VERSION 5.7 ;
BUSBITCHARS "[]" ;
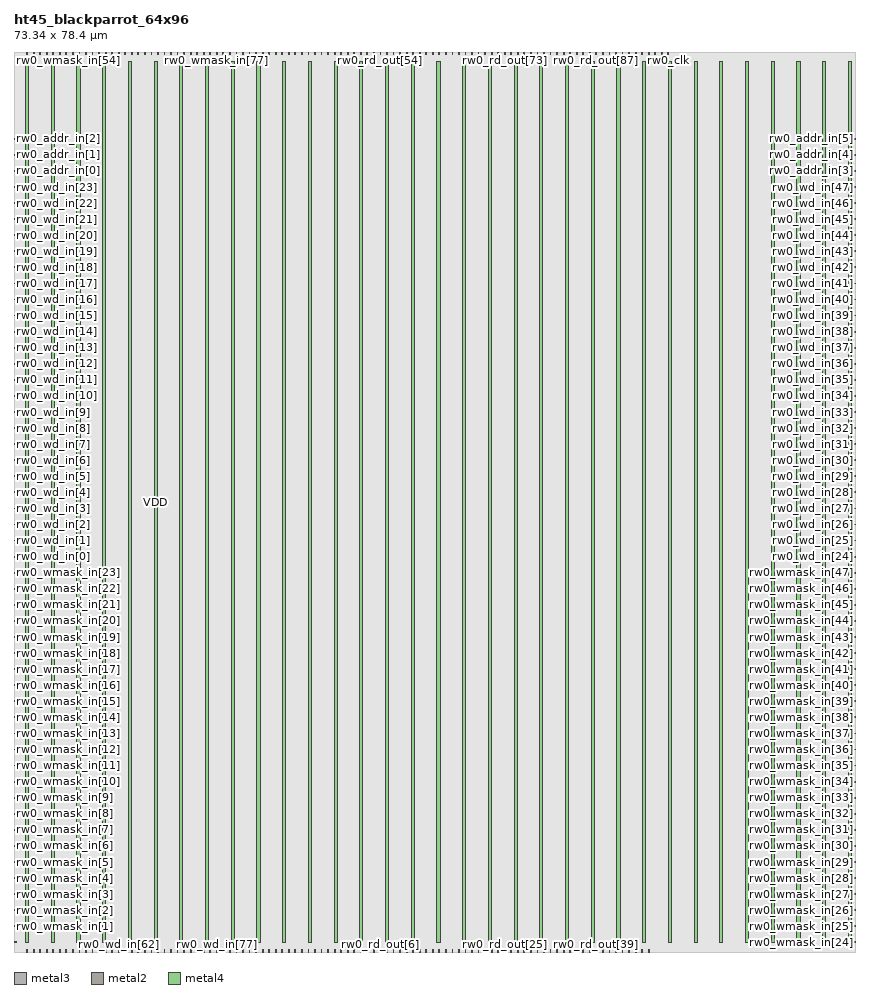
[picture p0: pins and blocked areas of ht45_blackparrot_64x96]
MACRO ht45_blackparrot_64x96
  FOREIGN ht45_blackparrot_64x96 0 0 ;
  SYMMETRY X Y R90 ;
  SIZE 73.340 BY 78.400 ;
  CLASS BLOCK ;
  PIN rw0_wmask_in[0]
    DIRECTION INPUT ;
    USE SIGNAL ;
    SHAPE ABUTMENT ;
    PORT
      LAYER metal3 ;
      RECT 0.000 0.805 0.210 0.875 ;
    END
  END rw0_wmask_in[0]
  PIN rw0_wmask_in[1]
    DIRECTION INPUT ;
    USE SIGNAL ;
    SHAPE ABUTMENT ;
    PORT
      LAYER metal3 ;
      RECT 0.000 2.205 0.210 2.275 ;
    END
  END rw0_wmask_in[1]
  PIN rw0_wmask_in[2]
    DIRECTION INPUT ;
    USE SIGNAL ;
    SHAPE ABUTMENT ;
    PORT
      LAYER metal3 ;
      RECT 0.000 3.605 0.210 3.675 ;
    END
  END rw0_wmask_in[2]
  PIN rw0_wmask_in[3]
    DIRECTION INPUT ;
    USE SIGNAL ;
    SHAPE ABUTMENT ;
    PORT
      LAYER metal3 ;
      RECT 0.000 5.005 0.210 5.075 ;
    END
  END rw0_wmask_in[3]
  PIN rw0_wmask_in[4]
    DIRECTION INPUT ;
    USE SIGNAL ;
    SHAPE ABUTMENT ;
    PORT
      LAYER metal3 ;
      RECT 0.000 6.405 0.210 6.475 ;
    END
  END rw0_wmask_in[4]
  PIN rw0_wmask_in[5]
    DIRECTION INPUT ;
    USE SIGNAL ;
    SHAPE ABUTMENT ;
    PORT
      LAYER metal3 ;
      RECT 0.000 7.805 0.210 7.875 ;
    END
  END rw0_wmask_in[5]
  PIN rw0_wmask_in[6]
    DIRECTION INPUT ;
    USE SIGNAL ;
    SHAPE ABUTMENT ;
    PORT
      LAYER metal3 ;
      RECT 0.000 9.205 0.210 9.275 ;
    END
  END rw0_wmask_in[6]
  PIN rw0_wmask_in[7]
    DIRECTION INPUT ;
    USE SIGNAL ;
    SHAPE ABUTMENT ;
    PORT
      LAYER metal3 ;
      RECT 0.000 10.605 0.210 10.675 ;
    END
  END rw0_wmask_in[7]
  PIN rw0_wmask_in[8]
    DIRECTION INPUT ;
    USE SIGNAL ;
    SHAPE ABUTMENT ;
    PORT
      LAYER metal3 ;
      RECT 0.000 12.005 0.210 12.075 ;
    END
  END rw0_wmask_in[8]
  PIN rw0_wmask_in[9]
    DIRECTION INPUT ;
    USE SIGNAL ;
    SHAPE ABUTMENT ;
    PORT
      LAYER metal3 ;
      RECT 0.000 13.405 0.210 13.475 ;
    END
  END rw0_wmask_in[9]
  PIN rw0_wmask_in[10]
    DIRECTION INPUT ;
    USE SIGNAL ;
    SHAPE ABUTMENT ;
    PORT
      LAYER metal3 ;
      RECT 0.000 14.805 0.210 14.875 ;
    END
  END rw0_wmask_in[10]
  PIN rw0_wmask_in[11]
    DIRECTION INPUT ;
    USE SIGNAL ;
    SHAPE ABUTMENT ;
    PORT
      LAYER metal3 ;
      RECT 0.000 16.205 0.210 16.275 ;
    END
  END rw0_wmask_in[11]
  PIN rw0_wmask_in[12]
    DIRECTION INPUT ;
    USE SIGNAL ;
    SHAPE ABUTMENT ;
    PORT
      LAYER metal3 ;
      RECT 0.000 17.605 0.210 17.675 ;
    END
  END rw0_wmask_in[12]
  PIN rw0_wmask_in[13]
    DIRECTION INPUT ;
    USE SIGNAL ;
    SHAPE ABUTMENT ;
    PORT
      LAYER metal3 ;
      RECT 0.000 19.005 0.210 19.075 ;
    END
  END rw0_wmask_in[13]
  PIN rw0_wmask_in[14]
    DIRECTION INPUT ;
    USE SIGNAL ;
    SHAPE ABUTMENT ;
    PORT
      LAYER metal3 ;
      RECT 0.000 20.405 0.210 20.475 ;
    END
  END rw0_wmask_in[14]
  PIN rw0_wmask_in[15]
    DIRECTION INPUT ;
    USE SIGNAL ;
    SHAPE ABUTMENT ;
    PORT
      LAYER metal3 ;
      RECT 0.000 21.805 0.210 21.875 ;
    END
  END rw0_wmask_in[15]
  PIN rw0_wmask_in[16]
    DIRECTION INPUT ;
    USE SIGNAL ;
    SHAPE ABUTMENT ;
    PORT
      LAYER metal3 ;
      RECT 0.000 23.205 0.210 23.275 ;
    END
  END rw0_wmask_in[16]
  PIN rw0_wmask_in[17]
    DIRECTION INPUT ;
    USE SIGNAL ;
    SHAPE ABUTMENT ;
    PORT
      LAYER metal3 ;
      RECT 0.000 24.605 0.210 24.675 ;
    END
  END rw0_wmask_in[17]
  PIN rw0_wmask_in[18]
    DIRECTION INPUT ;
    USE SIGNAL ;
    SHAPE ABUTMENT ;
    PORT
      LAYER metal3 ;
      RECT 0.000 26.005 0.210 26.075 ;
    END
  END rw0_wmask_in[18]
  PIN rw0_wmask_in[19]
    DIRECTION INPUT ;
    USE SIGNAL ;
    SHAPE ABUTMENT ;
    PORT
      LAYER metal3 ;
      RECT 0.000 27.405 0.210 27.475 ;
    END
  END rw0_wmask_in[19]
  PIN rw0_wmask_in[20]
    DIRECTION INPUT ;
    USE SIGNAL ;
    SHAPE ABUTMENT ;
    PORT
      LAYER metal3 ;
      RECT 0.000 28.805 0.210 28.875 ;
    END
  END rw0_wmask_in[20]
  PIN rw0_wmask_in[21]
    DIRECTION INPUT ;
    USE SIGNAL ;
    SHAPE ABUTMENT ;
    PORT
      LAYER metal3 ;
      RECT 0.000 30.205 0.210 30.275 ;
    END
  END rw0_wmask_in[21]
  PIN rw0_wmask_in[22]
    DIRECTION INPUT ;
    USE SIGNAL ;
    SHAPE ABUTMENT ;
    PORT
      LAYER metal3 ;
      RECT 0.000 31.605 0.210 31.675 ;
    END
  END rw0_wmask_in[22]
  PIN rw0_wmask_in[23]
    DIRECTION INPUT ;
    USE SIGNAL ;
    SHAPE ABUTMENT ;
    PORT
      LAYER metal3 ;
      RECT 0.000 33.005 0.210 33.075 ;
    END
  END rw0_wmask_in[23]
  PIN rw0_wmask_in[24]
    DIRECTION INPUT ;
    USE SIGNAL ;
    SHAPE ABUTMENT ;
    PORT
      LAYER metal3 ;
      RECT 73.130 0.805 73.340 0.875 ;
    END
  END rw0_wmask_in[24]
  PIN rw0_wmask_in[25]
    DIRECTION INPUT ;
    USE SIGNAL ;
    SHAPE ABUTMENT ;
    PORT
      LAYER metal3 ;
      RECT 73.130 2.205 73.340 2.275 ;
    END
  END rw0_wmask_in[25]
  PIN rw0_wmask_in[26]
    DIRECTION INPUT ;
    USE SIGNAL ;
    SHAPE ABUTMENT ;
    PORT
      LAYER metal3 ;
      RECT 73.130 3.605 73.340 3.675 ;
    END
  END rw0_wmask_in[26]
  PIN rw0_wmask_in[27]
    DIRECTION INPUT ;
    USE SIGNAL ;
    SHAPE ABUTMENT ;
    PORT
      LAYER metal3 ;
      RECT 73.130 5.005 73.340 5.075 ;
    END
  END rw0_wmask_in[27]
  PIN rw0_wmask_in[28]
    DIRECTION INPUT ;
    USE SIGNAL ;
    SHAPE ABUTMENT ;
    PORT
      LAYER metal3 ;
      RECT 73.130 6.405 73.340 6.475 ;
    END
  END rw0_wmask_in[28]
  PIN rw0_wmask_in[29]
    DIRECTION INPUT ;
    USE SIGNAL ;
    SHAPE ABUTMENT ;
    PORT
      LAYER metal3 ;
      RECT 73.130 7.805 73.340 7.875 ;
    END
  END rw0_wmask_in[29]
  PIN rw0_wmask_in[30]
    DIRECTION INPUT ;
    USE SIGNAL ;
    SHAPE ABUTMENT ;
    PORT
      LAYER metal3 ;
      RECT 73.130 9.205 73.340 9.275 ;
    END
  END rw0_wmask_in[30]
  PIN rw0_wmask_in[31]
    DIRECTION INPUT ;
    USE SIGNAL ;
    SHAPE ABUTMENT ;
    PORT
      LAYER metal3 ;
      RECT 73.130 10.605 73.340 10.675 ;
    END
  END rw0_wmask_in[31]
  PIN rw0_wmask_in[32]
    DIRECTION INPUT ;
    USE SIGNAL ;
    SHAPE ABUTMENT ;
    PORT
      LAYER metal3 ;
      RECT 73.130 12.005 73.340 12.075 ;
    END
  END rw0_wmask_in[32]
  PIN rw0_wmask_in[33]
    DIRECTION INPUT ;
    USE SIGNAL ;
    SHAPE ABUTMENT ;
    PORT
      LAYER metal3 ;
      RECT 73.130 13.405 73.340 13.475 ;
    END
  END rw0_wmask_in[33]
  PIN rw0_wmask_in[34]
    DIRECTION INPUT ;
    USE SIGNAL ;
    SHAPE ABUTMENT ;
    PORT
      LAYER metal3 ;
      RECT 73.130 14.805 73.340 14.875 ;
    END
  END rw0_wmask_in[34]
  PIN rw0_wmask_in[35]
    DIRECTION INPUT ;
    USE SIGNAL ;
    SHAPE ABUTMENT ;
    PORT
      LAYER metal3 ;
      RECT 73.130 16.205 73.340 16.275 ;
    END
  END rw0_wmask_in[35]
  PIN rw0_wmask_in[36]
    DIRECTION INPUT ;
    USE SIGNAL ;
    SHAPE ABUTMENT ;
    PORT
      LAYER metal3 ;
      RECT 73.130 17.605 73.340 17.675 ;
    END
  END rw0_wmask_in[36]
  PIN rw0_wmask_in[37]
    DIRECTION INPUT ;
    USE SIGNAL ;
    SHAPE ABUTMENT ;
    PORT
      LAYER metal3 ;
      RECT 73.130 19.005 73.340 19.075 ;
    END
  END rw0_wmask_in[37]
  PIN rw0_wmask_in[38]
    DIRECTION INPUT ;
    USE SIGNAL ;
    SHAPE ABUTMENT ;
    PORT
      LAYER metal3 ;
      RECT 73.130 20.405 73.340 20.475 ;
    END
  END rw0_wmask_in[38]
  PIN rw0_wmask_in[39]
    DIRECTION INPUT ;
    USE SIGNAL ;
    SHAPE ABUTMENT ;
    PORT
      LAYER metal3 ;
      RECT 73.130 21.805 73.340 21.875 ;
    END
  END rw0_wmask_in[39]
  PIN rw0_wmask_in[40]
    DIRECTION INPUT ;
    USE SIGNAL ;
    SHAPE ABUTMENT ;
    PORT
      LAYER metal3 ;
      RECT 73.130 23.205 73.340 23.275 ;
    END
  END rw0_wmask_in[40]
  PIN rw0_wmask_in[41]
    DIRECTION INPUT ;
    USE SIGNAL ;
    SHAPE ABUTMENT ;
    PORT
      LAYER metal3 ;
      RECT 73.130 24.605 73.340 24.675 ;
    END
  END rw0_wmask_in[41]
  PIN rw0_wmask_in[42]
    DIRECTION INPUT ;
    USE SIGNAL ;
    SHAPE ABUTMENT ;
    PORT
      LAYER metal3 ;
      RECT 73.130 26.005 73.340 26.075 ;
    END
  END rw0_wmask_in[42]
  PIN rw0_wmask_in[43]
    DIRECTION INPUT ;
    USE SIGNAL ;
    SHAPE ABUTMENT ;
    PORT
      LAYER metal3 ;
      RECT 73.130 27.405 73.340 27.475 ;
    END
  END rw0_wmask_in[43]
  PIN rw0_wmask_in[44]
    DIRECTION INPUT ;
    USE SIGNAL ;
    SHAPE ABUTMENT ;
    PORT
      LAYER metal3 ;
      RECT 73.130 28.805 73.340 28.875 ;
    END
  END rw0_wmask_in[44]
  PIN rw0_wmask_in[45]
    DIRECTION INPUT ;
    USE SIGNAL ;
    SHAPE ABUTMENT ;
    PORT
      LAYER metal3 ;
      RECT 73.130 30.205 73.340 30.275 ;
    END
  END rw0_wmask_in[45]
  PIN rw0_wmask_in[46]
    DIRECTION INPUT ;
    USE SIGNAL ;
    SHAPE ABUTMENT ;
    PORT
      LAYER metal3 ;
      RECT 73.130 31.605 73.340 31.675 ;
    END
  END rw0_wmask_in[46]
  PIN rw0_wmask_in[47]
    DIRECTION INPUT ;
    USE SIGNAL ;
    SHAPE ABUTMENT ;
    PORT
      LAYER metal3 ;
      RECT 73.130 33.005 73.340 33.075 ;
    END
  END rw0_wmask_in[47]
  PIN rw0_wmask_in[48]
    DIRECTION INPUT ;
    USE SIGNAL ;
    SHAPE ABUTMENT ;
    PORT
      LAYER metal2 ;
      RECT 1.105 78.190 1.175 78.400 ;
    END
  END rw0_wmask_in[48]
  PIN rw0_wmask_in[49]
    DIRECTION INPUT ;
    USE SIGNAL ;
    SHAPE ABUTMENT ;
    PORT
      LAYER metal2 ;
      RECT 1.675 78.190 1.745 78.400 ;
    END
  END rw0_wmask_in[49]
  PIN rw0_wmask_in[50]
    DIRECTION INPUT ;
    USE SIGNAL ;
    SHAPE ABUTMENT ;
    PORT
      LAYER metal2 ;
      RECT 2.245 78.190 2.315 78.400 ;
    END
  END rw0_wmask_in[50]
  PIN rw0_wmask_in[51]
    DIRECTION INPUT ;
    USE SIGNAL ;
    SHAPE ABUTMENT ;
    PORT
      LAYER metal2 ;
      RECT 2.815 78.190 2.885 78.400 ;
    END
  END rw0_wmask_in[51]
  PIN rw0_wmask_in[52]
    DIRECTION INPUT ;
    USE SIGNAL ;
    SHAPE ABUTMENT ;
    PORT
      LAYER metal2 ;
      RECT 3.385 78.190 3.455 78.400 ;
    END
  END rw0_wmask_in[52]
  PIN rw0_wmask_in[53]
    DIRECTION INPUT ;
    USE SIGNAL ;
    SHAPE ABUTMENT ;
    PORT
      LAYER metal2 ;
      RECT 3.955 78.190 4.025 78.400 ;
    END
  END rw0_wmask_in[53]
  PIN rw0_wmask_in[54]
    DIRECTION INPUT ;
    USE SIGNAL ;
    SHAPE ABUTMENT ;
    PORT
      LAYER metal2 ;
      RECT 4.525 78.190 4.595 78.400 ;
    END
  END rw0_wmask_in[54]
  PIN rw0_wmask_in[55]
    DIRECTION INPUT ;
    USE SIGNAL ;
    SHAPE ABUTMENT ;
    PORT
      LAYER metal2 ;
      RECT 5.095 78.190 5.165 78.400 ;
    END
  END rw0_wmask_in[55]
  PIN rw0_wmask_in[56]
    DIRECTION INPUT ;
    USE SIGNAL ;
    SHAPE ABUTMENT ;
    PORT
      LAYER metal2 ;
      RECT 5.665 78.190 5.735 78.400 ;
    END
  END rw0_wmask_in[56]
  PIN rw0_wmask_in[57]
    DIRECTION INPUT ;
    USE SIGNAL ;
    SHAPE ABUTMENT ;
    PORT
      LAYER metal2 ;
      RECT 6.235 78.190 6.305 78.400 ;
    END
  END rw0_wmask_in[57]
  PIN rw0_wmask_in[58]
    DIRECTION INPUT ;
    USE SIGNAL ;
    SHAPE ABUTMENT ;
    PORT
      LAYER metal2 ;
      RECT 6.805 78.190 6.875 78.400 ;
    END
  END rw0_wmask_in[58]
  PIN rw0_wmask_in[59]
    DIRECTION INPUT ;
    USE SIGNAL ;
    SHAPE ABUTMENT ;
    PORT
      LAYER metal2 ;
      RECT 7.375 78.190 7.445 78.400 ;
    END
  END rw0_wmask_in[59]
  PIN rw0_wmask_in[60]
    DIRECTION INPUT ;
    USE SIGNAL ;
    SHAPE ABUTMENT ;
    PORT
      LAYER metal2 ;
      RECT 7.945 78.190 8.015 78.400 ;
    END
  END rw0_wmask_in[60]
  PIN rw0_wmask_in[61]
    DIRECTION INPUT ;
    USE SIGNAL ;
    SHAPE ABUTMENT ;
    PORT
      LAYER metal2 ;
      RECT 8.515 78.190 8.585 78.400 ;
    END
  END rw0_wmask_in[61]
  PIN rw0_wmask_in[62]
    DIRECTION INPUT ;
    USE SIGNAL ;
    SHAPE ABUTMENT ;
    PORT
      LAYER metal2 ;
      RECT 9.085 78.190 9.155 78.400 ;
    END
  END rw0_wmask_in[62]
  PIN rw0_wmask_in[63]
    DIRECTION INPUT ;
    USE SIGNAL ;
    SHAPE ABUTMENT ;
    PORT
      LAYER metal2 ;
      RECT 9.655 78.190 9.725 78.400 ;
    END
  END rw0_wmask_in[63]
  PIN rw0_wmask_in[64]
    DIRECTION INPUT ;
    USE SIGNAL ;
    SHAPE ABUTMENT ;
    PORT
      LAYER metal2 ;
      RECT 10.225 78.190 10.295 78.400 ;
    END
  END rw0_wmask_in[64]
  PIN rw0_wmask_in[65]
    DIRECTION INPUT ;
    USE SIGNAL ;
    SHAPE ABUTMENT ;
    PORT
      LAYER metal2 ;
      RECT 10.795 78.190 10.865 78.400 ;
    END
  END rw0_wmask_in[65]
  PIN rw0_wmask_in[66]
    DIRECTION INPUT ;
    USE SIGNAL ;
    SHAPE ABUTMENT ;
    PORT
      LAYER metal2 ;
      RECT 11.365 78.190 11.435 78.400 ;
    END
  END rw0_wmask_in[66]
  PIN rw0_wmask_in[67]
    DIRECTION INPUT ;
    USE SIGNAL ;
    SHAPE ABUTMENT ;
    PORT
      LAYER metal2 ;
      RECT 11.935 78.190 12.005 78.400 ;
    END
  END rw0_wmask_in[67]
  PIN rw0_wmask_in[68]
    DIRECTION INPUT ;
    USE SIGNAL ;
    SHAPE ABUTMENT ;
    PORT
      LAYER metal2 ;
      RECT 12.505 78.190 12.575 78.400 ;
    END
  END rw0_wmask_in[68]
  PIN rw0_wmask_in[69]
    DIRECTION INPUT ;
    USE SIGNAL ;
    SHAPE ABUTMENT ;
    PORT
      LAYER metal2 ;
      RECT 13.075 78.190 13.145 78.400 ;
    END
  END rw0_wmask_in[69]
  PIN rw0_wmask_in[70]
    DIRECTION INPUT ;
    USE SIGNAL ;
    SHAPE ABUTMENT ;
    PORT
      LAYER metal2 ;
      RECT 13.645 78.190 13.715 78.400 ;
    END
  END rw0_wmask_in[70]
  PIN rw0_wmask_in[71]
    DIRECTION INPUT ;
    USE SIGNAL ;
    SHAPE ABUTMENT ;
    PORT
      LAYER metal2 ;
      RECT 14.215 78.190 14.285 78.400 ;
    END
  END rw0_wmask_in[71]
  PIN rw0_wmask_in[72]
    DIRECTION INPUT ;
    USE SIGNAL ;
    SHAPE ABUTMENT ;
    PORT
      LAYER metal2 ;
      RECT 14.785 78.190 14.855 78.400 ;
    END
  END rw0_wmask_in[72]
  PIN rw0_wmask_in[73]
    DIRECTION INPUT ;
    USE SIGNAL ;
    SHAPE ABUTMENT ;
    PORT
      LAYER metal2 ;
      RECT 15.355 78.190 15.425 78.400 ;
    END
  END rw0_wmask_in[73]
  PIN rw0_wmask_in[74]
    DIRECTION INPUT ;
    USE SIGNAL ;
    SHAPE ABUTMENT ;
    PORT
      LAYER metal2 ;
      RECT 15.925 78.190 15.995 78.400 ;
    END
  END rw0_wmask_in[74]
  PIN rw0_wmask_in[75]
    DIRECTION INPUT ;
    USE SIGNAL ;
    SHAPE ABUTMENT ;
    PORT
      LAYER metal2 ;
      RECT 16.495 78.190 16.565 78.400 ;
    END
  END rw0_wmask_in[75]
  PIN rw0_wmask_in[76]
    DIRECTION INPUT ;
    USE SIGNAL ;
    SHAPE ABUTMENT ;
    PORT
      LAYER metal2 ;
      RECT 17.065 78.190 17.135 78.400 ;
    END
  END rw0_wmask_in[76]
  PIN rw0_wmask_in[77]
    DIRECTION INPUT ;
    USE SIGNAL ;
    SHAPE ABUTMENT ;
    PORT
      LAYER metal2 ;
      RECT 17.635 78.190 17.705 78.400 ;
    END
  END rw0_wmask_in[77]
  PIN rw0_wmask_in[78]
    DIRECTION INPUT ;
    USE SIGNAL ;
    SHAPE ABUTMENT ;
    PORT
      LAYER metal2 ;
      RECT 18.205 78.190 18.275 78.400 ;
    END
  END rw0_wmask_in[78]
  PIN rw0_wmask_in[79]
    DIRECTION INPUT ;
    USE SIGNAL ;
    SHAPE ABUTMENT ;
    PORT
      LAYER metal2 ;
      RECT 18.775 78.190 18.845 78.400 ;
    END
  END rw0_wmask_in[79]
  PIN rw0_wmask_in[80]
    DIRECTION INPUT ;
    USE SIGNAL ;
    SHAPE ABUTMENT ;
    PORT
      LAYER metal2 ;
      RECT 19.345 78.190 19.415 78.400 ;
    END
  END rw0_wmask_in[80]
  PIN rw0_wmask_in[81]
    DIRECTION INPUT ;
    USE SIGNAL ;
    SHAPE ABUTMENT ;
    PORT
      LAYER metal2 ;
      RECT 19.915 78.190 19.985 78.400 ;
    END
  END rw0_wmask_in[81]
  PIN rw0_wmask_in[82]
    DIRECTION INPUT ;
    USE SIGNAL ;
    SHAPE ABUTMENT ;
    PORT
      LAYER metal2 ;
      RECT 20.485 78.190 20.555 78.400 ;
    END
  END rw0_wmask_in[82]
  PIN rw0_wmask_in[83]
    DIRECTION INPUT ;
    USE SIGNAL ;
    SHAPE ABUTMENT ;
    PORT
      LAYER metal2 ;
      RECT 21.055 78.190 21.125 78.400 ;
    END
  END rw0_wmask_in[83]
  PIN rw0_wmask_in[84]
    DIRECTION INPUT ;
    USE SIGNAL ;
    SHAPE ABUTMENT ;
    PORT
      LAYER metal2 ;
      RECT 21.625 78.190 21.695 78.400 ;
    END
  END rw0_wmask_in[84]
  PIN rw0_wmask_in[85]
    DIRECTION INPUT ;
    USE SIGNAL ;
    SHAPE ABUTMENT ;
    PORT
      LAYER metal2 ;
      RECT 22.195 78.190 22.265 78.400 ;
    END
  END rw0_wmask_in[85]
  PIN rw0_wmask_in[86]
    DIRECTION INPUT ;
    USE SIGNAL ;
    SHAPE ABUTMENT ;
    PORT
      LAYER metal2 ;
      RECT 22.765 78.190 22.835 78.400 ;
    END
  END rw0_wmask_in[86]
  PIN rw0_wmask_in[87]
    DIRECTION INPUT ;
    USE SIGNAL ;
    SHAPE ABUTMENT ;
    PORT
      LAYER metal2 ;
      RECT 23.335 78.190 23.405 78.400 ;
    END
  END rw0_wmask_in[87]
  PIN rw0_wmask_in[88]
    DIRECTION INPUT ;
    USE SIGNAL ;
    SHAPE ABUTMENT ;
    PORT
      LAYER metal2 ;
      RECT 23.905 78.190 23.975 78.400 ;
    END
  END rw0_wmask_in[88]
  PIN rw0_wmask_in[89]
    DIRECTION INPUT ;
    USE SIGNAL ;
    SHAPE ABUTMENT ;
    PORT
      LAYER metal2 ;
      RECT 24.475 78.190 24.545 78.400 ;
    END
  END rw0_wmask_in[89]
  PIN rw0_wmask_in[90]
    DIRECTION INPUT ;
    USE SIGNAL ;
    SHAPE ABUTMENT ;
    PORT
      LAYER metal2 ;
      RECT 25.045 78.190 25.115 78.400 ;
    END
  END rw0_wmask_in[90]
  PIN rw0_wmask_in[91]
    DIRECTION INPUT ;
    USE SIGNAL ;
    SHAPE ABUTMENT ;
    PORT
      LAYER metal2 ;
      RECT 25.615 78.190 25.685 78.400 ;
    END
  END rw0_wmask_in[91]
  PIN rw0_wmask_in[92]
    DIRECTION INPUT ;
    USE SIGNAL ;
    SHAPE ABUTMENT ;
    PORT
      LAYER metal2 ;
      RECT 26.185 78.190 26.255 78.400 ;
    END
  END rw0_wmask_in[92]
  PIN rw0_wmask_in[93]
    DIRECTION INPUT ;
    USE SIGNAL ;
    SHAPE ABUTMENT ;
    PORT
      LAYER metal2 ;
      RECT 26.755 78.190 26.825 78.400 ;
    END
  END rw0_wmask_in[93]
  PIN rw0_wmask_in[94]
    DIRECTION INPUT ;
    USE SIGNAL ;
    SHAPE ABUTMENT ;
    PORT
      LAYER metal2 ;
      RECT 27.325 78.190 27.395 78.400 ;
    END
  END rw0_wmask_in[94]
  PIN rw0_wmask_in[95]
    DIRECTION INPUT ;
    USE SIGNAL ;
    SHAPE ABUTMENT ;
    PORT
      LAYER metal2 ;
      RECT 27.895 78.190 27.965 78.400 ;
    END
  END rw0_wmask_in[95]
  PIN rw0_wd_in[0]
    DIRECTION INPUT ;
    USE SIGNAL ;
    SHAPE ABUTMENT ;
    PORT
      LAYER metal3 ;
      RECT 0.000 34.405 0.210 34.475 ;
    END
  END rw0_wd_in[0]
  PIN rw0_wd_in[1]
    DIRECTION INPUT ;
    USE SIGNAL ;
    SHAPE ABUTMENT ;
    PORT
      LAYER metal3 ;
      RECT 0.000 35.805 0.210 35.875 ;
    END
  END rw0_wd_in[1]
  PIN rw0_wd_in[2]
    DIRECTION INPUT ;
    USE SIGNAL ;
    SHAPE ABUTMENT ;
    PORT
      LAYER metal3 ;
      RECT 0.000 37.205 0.210 37.275 ;
    END
  END rw0_wd_in[2]
  PIN rw0_wd_in[3]
    DIRECTION INPUT ;
    USE SIGNAL ;
    SHAPE ABUTMENT ;
    PORT
      LAYER metal3 ;
      RECT 0.000 38.605 0.210 38.675 ;
    END
  END rw0_wd_in[3]
  PIN rw0_wd_in[4]
    DIRECTION INPUT ;
    USE SIGNAL ;
    SHAPE ABUTMENT ;
    PORT
      LAYER metal3 ;
      RECT 0.000 40.005 0.210 40.075 ;
    END
  END rw0_wd_in[4]
  PIN rw0_wd_in[5]
    DIRECTION INPUT ;
    USE SIGNAL ;
    SHAPE ABUTMENT ;
    PORT
      LAYER metal3 ;
      RECT 0.000 41.405 0.210 41.475 ;
    END
  END rw0_wd_in[5]
  PIN rw0_wd_in[6]
    DIRECTION INPUT ;
    USE SIGNAL ;
    SHAPE ABUTMENT ;
    PORT
      LAYER metal3 ;
      RECT 0.000 42.805 0.210 42.875 ;
    END
  END rw0_wd_in[6]
  PIN rw0_wd_in[7]
    DIRECTION INPUT ;
    USE SIGNAL ;
    SHAPE ABUTMENT ;
    PORT
      LAYER metal3 ;
      RECT 0.000 44.205 0.210 44.275 ;
    END
  END rw0_wd_in[7]
  PIN rw0_wd_in[8]
    DIRECTION INPUT ;
    USE SIGNAL ;
    SHAPE ABUTMENT ;
    PORT
      LAYER metal3 ;
      RECT 0.000 45.605 0.210 45.675 ;
    END
  END rw0_wd_in[8]
  PIN rw0_wd_in[9]
    DIRECTION INPUT ;
    USE SIGNAL ;
    SHAPE ABUTMENT ;
    PORT
      LAYER metal3 ;
      RECT 0.000 47.005 0.210 47.075 ;
    END
  END rw0_wd_in[9]
  PIN rw0_wd_in[10]
    DIRECTION INPUT ;
    USE SIGNAL ;
    SHAPE ABUTMENT ;
    PORT
      LAYER metal3 ;
      RECT 0.000 48.405 0.210 48.475 ;
    END
  END rw0_wd_in[10]
  PIN rw0_wd_in[11]
    DIRECTION INPUT ;
    USE SIGNAL ;
    SHAPE ABUTMENT ;
    PORT
      LAYER metal3 ;
      RECT 0.000 49.805 0.210 49.875 ;
    END
  END rw0_wd_in[11]
  PIN rw0_wd_in[12]
    DIRECTION INPUT ;
    USE SIGNAL ;
    SHAPE ABUTMENT ;
    PORT
      LAYER metal3 ;
      RECT 0.000 51.205 0.210 51.275 ;
    END
  END rw0_wd_in[12]
  PIN rw0_wd_in[13]
    DIRECTION INPUT ;
    USE SIGNAL ;
    SHAPE ABUTMENT ;
    PORT
      LAYER metal3 ;
      RECT 0.000 52.605 0.210 52.675 ;
    END
  END rw0_wd_in[13]
  PIN rw0_wd_in[14]
    DIRECTION INPUT ;
    USE SIGNAL ;
    SHAPE ABUTMENT ;
    PORT
      LAYER metal3 ;
      RECT 0.000 54.005 0.210 54.075 ;
    END
  END rw0_wd_in[14]
  PIN rw0_wd_in[15]
    DIRECTION INPUT ;
    USE SIGNAL ;
    SHAPE ABUTMENT ;
    PORT
      LAYER metal3 ;
      RECT 0.000 55.405 0.210 55.475 ;
    END
  END rw0_wd_in[15]
  PIN rw0_wd_in[16]
    DIRECTION INPUT ;
    USE SIGNAL ;
    SHAPE ABUTMENT ;
    PORT
      LAYER metal3 ;
      RECT 0.000 56.805 0.210 56.875 ;
    END
  END rw0_wd_in[16]
  PIN rw0_wd_in[17]
    DIRECTION INPUT ;
    USE SIGNAL ;
    SHAPE ABUTMENT ;
    PORT
      LAYER metal3 ;
      RECT 0.000 58.205 0.210 58.275 ;
    END
  END rw0_wd_in[17]
  PIN rw0_wd_in[18]
    DIRECTION INPUT ;
    USE SIGNAL ;
    SHAPE ABUTMENT ;
    PORT
      LAYER metal3 ;
      RECT 0.000 59.605 0.210 59.675 ;
    END
  END rw0_wd_in[18]
  PIN rw0_wd_in[19]
    DIRECTION INPUT ;
    USE SIGNAL ;
    SHAPE ABUTMENT ;
    PORT
      LAYER metal3 ;
      RECT 0.000 61.005 0.210 61.075 ;
    END
  END rw0_wd_in[19]
  PIN rw0_wd_in[20]
    DIRECTION INPUT ;
    USE SIGNAL ;
    SHAPE ABUTMENT ;
    PORT
      LAYER metal3 ;
      RECT 0.000 62.405 0.210 62.475 ;
    END
  END rw0_wd_in[20]
  PIN rw0_wd_in[21]
    DIRECTION INPUT ;
    USE SIGNAL ;
    SHAPE ABUTMENT ;
    PORT
      LAYER metal3 ;
      RECT 0.000 63.805 0.210 63.875 ;
    END
  END rw0_wd_in[21]
  PIN rw0_wd_in[22]
    DIRECTION INPUT ;
    USE SIGNAL ;
    SHAPE ABUTMENT ;
    PORT
      LAYER metal3 ;
      RECT 0.000 65.205 0.210 65.275 ;
    END
  END rw0_wd_in[22]
  PIN rw0_wd_in[23]
    DIRECTION INPUT ;
    USE SIGNAL ;
    SHAPE ABUTMENT ;
    PORT
      LAYER metal3 ;
      RECT 0.000 66.605 0.210 66.675 ;
    END
  END rw0_wd_in[23]
  PIN rw0_wd_in[24]
    DIRECTION INPUT ;
    USE SIGNAL ;
    SHAPE ABUTMENT ;
    PORT
      LAYER metal3 ;
      RECT 73.130 34.405 73.340 34.475 ;
    END
  END rw0_wd_in[24]
  PIN rw0_wd_in[25]
    DIRECTION INPUT ;
    USE SIGNAL ;
    SHAPE ABUTMENT ;
    PORT
      LAYER metal3 ;
      RECT 73.130 35.805 73.340 35.875 ;
    END
  END rw0_wd_in[25]
  PIN rw0_wd_in[26]
    DIRECTION INPUT ;
    USE SIGNAL ;
    SHAPE ABUTMENT ;
    PORT
      LAYER metal3 ;
      RECT 73.130 37.205 73.340 37.275 ;
    END
  END rw0_wd_in[26]
  PIN rw0_wd_in[27]
    DIRECTION INPUT ;
    USE SIGNAL ;
    SHAPE ABUTMENT ;
    PORT
      LAYER metal3 ;
      RECT 73.130 38.605 73.340 38.675 ;
    END
  END rw0_wd_in[27]
  PIN rw0_wd_in[28]
    DIRECTION INPUT ;
    USE SIGNAL ;
    SHAPE ABUTMENT ;
    PORT
      LAYER metal3 ;
      RECT 73.130 40.005 73.340 40.075 ;
    END
  END rw0_wd_in[28]
  PIN rw0_wd_in[29]
    DIRECTION INPUT ;
    USE SIGNAL ;
    SHAPE ABUTMENT ;
    PORT
      LAYER metal3 ;
      RECT 73.130 41.405 73.340 41.475 ;
    END
  END rw0_wd_in[29]
  PIN rw0_wd_in[30]
    DIRECTION INPUT ;
    USE SIGNAL ;
    SHAPE ABUTMENT ;
    PORT
      LAYER metal3 ;
      RECT 73.130 42.805 73.340 42.875 ;
    END
  END rw0_wd_in[30]
  PIN rw0_wd_in[31]
    DIRECTION INPUT ;
    USE SIGNAL ;
    SHAPE ABUTMENT ;
    PORT
      LAYER metal3 ;
      RECT 73.130 44.205 73.340 44.275 ;
    END
  END rw0_wd_in[31]
  PIN rw0_wd_in[32]
    DIRECTION INPUT ;
    USE SIGNAL ;
    SHAPE ABUTMENT ;
    PORT
      LAYER metal3 ;
      RECT 73.130 45.605 73.340 45.675 ;
    END
  END rw0_wd_in[32]
  PIN rw0_wd_in[33]
    DIRECTION INPUT ;
    USE SIGNAL ;
    SHAPE ABUTMENT ;
    PORT
      LAYER metal3 ;
      RECT 73.130 47.005 73.340 47.075 ;
    END
  END rw0_wd_in[33]
  PIN rw0_wd_in[34]
    DIRECTION INPUT ;
    USE SIGNAL ;
    SHAPE ABUTMENT ;
    PORT
      LAYER metal3 ;
      RECT 73.130 48.405 73.340 48.475 ;
    END
  END rw0_wd_in[34]
  PIN rw0_wd_in[35]
    DIRECTION INPUT ;
    USE SIGNAL ;
    SHAPE ABUTMENT ;
    PORT
      LAYER metal3 ;
      RECT 73.130 49.805 73.340 49.875 ;
    END
  END rw0_wd_in[35]
  PIN rw0_wd_in[36]
    DIRECTION INPUT ;
    USE SIGNAL ;
    SHAPE ABUTMENT ;
    PORT
      LAYER metal3 ;
      RECT 73.130 51.205 73.340 51.275 ;
    END
  END rw0_wd_in[36]
  PIN rw0_wd_in[37]
    DIRECTION INPUT ;
    USE SIGNAL ;
    SHAPE ABUTMENT ;
    PORT
      LAYER metal3 ;
      RECT 73.130 52.605 73.340 52.675 ;
    END
  END rw0_wd_in[37]
  PIN rw0_wd_in[38]
    DIRECTION INPUT ;
    USE SIGNAL ;
    SHAPE ABUTMENT ;
    PORT
      LAYER metal3 ;
      RECT 73.130 54.005 73.340 54.075 ;
    END
  END rw0_wd_in[38]
  PIN rw0_wd_in[39]
    DIRECTION INPUT ;
    USE SIGNAL ;
    SHAPE ABUTMENT ;
    PORT
      LAYER metal3 ;
      RECT 73.130 55.405 73.340 55.475 ;
    END
  END rw0_wd_in[39]
  PIN rw0_wd_in[40]
    DIRECTION INPUT ;
    USE SIGNAL ;
    SHAPE ABUTMENT ;
    PORT
      LAYER metal3 ;
      RECT 73.130 56.805 73.340 56.875 ;
    END
  END rw0_wd_in[40]
  PIN rw0_wd_in[41]
    DIRECTION INPUT ;
    USE SIGNAL ;
    SHAPE ABUTMENT ;
    PORT
      LAYER metal3 ;
      RECT 73.130 58.205 73.340 58.275 ;
    END
  END rw0_wd_in[41]
  PIN rw0_wd_in[42]
    DIRECTION INPUT ;
    USE SIGNAL ;
    SHAPE ABUTMENT ;
    PORT
      LAYER metal3 ;
      RECT 73.130 59.605 73.340 59.675 ;
    END
  END rw0_wd_in[42]
  PIN rw0_wd_in[43]
    DIRECTION INPUT ;
    USE SIGNAL ;
    SHAPE ABUTMENT ;
    PORT
      LAYER metal3 ;
      RECT 73.130 61.005 73.340 61.075 ;
    END
  END rw0_wd_in[43]
  PIN rw0_wd_in[44]
    DIRECTION INPUT ;
    USE SIGNAL ;
    SHAPE ABUTMENT ;
    PORT
      LAYER metal3 ;
      RECT 73.130 62.405 73.340 62.475 ;
    END
  END rw0_wd_in[44]
  PIN rw0_wd_in[45]
    DIRECTION INPUT ;
    USE SIGNAL ;
    SHAPE ABUTMENT ;
    PORT
      LAYER metal3 ;
      RECT 73.130 63.805 73.340 63.875 ;
    END
  END rw0_wd_in[45]
  PIN rw0_wd_in[46]
    DIRECTION INPUT ;
    USE SIGNAL ;
    SHAPE ABUTMENT ;
    PORT
      LAYER metal3 ;
      RECT 73.130 65.205 73.340 65.275 ;
    END
  END rw0_wd_in[46]
  PIN rw0_wd_in[47]
    DIRECTION INPUT ;
    USE SIGNAL ;
    SHAPE ABUTMENT ;
    PORT
      LAYER metal3 ;
      RECT 73.130 66.605 73.340 66.675 ;
    END
  END rw0_wd_in[47]
  PIN rw0_wd_in[48]
    DIRECTION INPUT ;
    USE SIGNAL ;
    SHAPE ABUTMENT ;
    PORT
      LAYER metal2 ;
      RECT 1.105 0.000 1.175 0.210 ;
    END
  END rw0_wd_in[48]
  PIN rw0_wd_in[49]
    DIRECTION INPUT ;
    USE SIGNAL ;
    SHAPE ABUTMENT ;
    PORT
      LAYER metal2 ;
      RECT 1.675 0.000 1.745 0.210 ;
    END
  END rw0_wd_in[49]
  PIN rw0_wd_in[50]
    DIRECTION INPUT ;
    USE SIGNAL ;
    SHAPE ABUTMENT ;
    PORT
      LAYER metal2 ;
      RECT 2.245 0.000 2.315 0.210 ;
    END
  END rw0_wd_in[50]
  PIN rw0_wd_in[51]
    DIRECTION INPUT ;
    USE SIGNAL ;
    SHAPE ABUTMENT ;
    PORT
      LAYER metal2 ;
      RECT 2.815 0.000 2.885 0.210 ;
    END
  END rw0_wd_in[51]
  PIN rw0_wd_in[52]
    DIRECTION INPUT ;
    USE SIGNAL ;
    SHAPE ABUTMENT ;
    PORT
      LAYER metal2 ;
      RECT 3.385 0.000 3.455 0.210 ;
    END
  END rw0_wd_in[52]
  PIN rw0_wd_in[53]
    DIRECTION INPUT ;
    USE SIGNAL ;
    SHAPE ABUTMENT ;
    PORT
      LAYER metal2 ;
      RECT 3.955 0.000 4.025 0.210 ;
    END
  END rw0_wd_in[53]
  PIN rw0_wd_in[54]
    DIRECTION INPUT ;
    USE SIGNAL ;
    SHAPE ABUTMENT ;
    PORT
      LAYER metal2 ;
      RECT 4.525 0.000 4.595 0.210 ;
    END
  END rw0_wd_in[54]
  PIN rw0_wd_in[55]
    DIRECTION INPUT ;
    USE SIGNAL ;
    SHAPE ABUTMENT ;
    PORT
      LAYER metal2 ;
      RECT 5.095 0.000 5.165 0.210 ;
    END
  END rw0_wd_in[55]
  PIN rw0_wd_in[56]
    DIRECTION INPUT ;
    USE SIGNAL ;
    SHAPE ABUTMENT ;
    PORT
      LAYER metal2 ;
      RECT 5.665 0.000 5.735 0.210 ;
    END
  END rw0_wd_in[56]
  PIN rw0_wd_in[57]
    DIRECTION INPUT ;
    USE SIGNAL ;
    SHAPE ABUTMENT ;
    PORT
      LAYER metal2 ;
      RECT 6.235 0.000 6.305 0.210 ;
    END
  END rw0_wd_in[57]
  PIN rw0_wd_in[58]
    DIRECTION INPUT ;
    USE SIGNAL ;
    SHAPE ABUTMENT ;
    PORT
      LAYER metal2 ;
      RECT 6.805 0.000 6.875 0.210 ;
    END
  END rw0_wd_in[58]
  PIN rw0_wd_in[59]
    DIRECTION INPUT ;
    USE SIGNAL ;
    SHAPE ABUTMENT ;
    PORT
      LAYER metal2 ;
      RECT 7.375 0.000 7.445 0.210 ;
    END
  END rw0_wd_in[59]
  PIN rw0_wd_in[60]
    DIRECTION INPUT ;
    USE SIGNAL ;
    SHAPE ABUTMENT ;
    PORT
      LAYER metal2 ;
      RECT 7.945 0.000 8.015 0.210 ;
    END
  END rw0_wd_in[60]
  PIN rw0_wd_in[61]
    DIRECTION INPUT ;
    USE SIGNAL ;
    SHAPE ABUTMENT ;
    PORT
      LAYER metal2 ;
      RECT 8.515 0.000 8.585 0.210 ;
    END
  END rw0_wd_in[61]
  PIN rw0_wd_in[62]
    DIRECTION INPUT ;
    USE SIGNAL ;
    SHAPE ABUTMENT ;
    PORT
      LAYER metal2 ;
      RECT 9.085 0.000 9.155 0.210 ;
    END
  END rw0_wd_in[62]
  PIN rw0_wd_in[63]
    DIRECTION INPUT ;
    USE SIGNAL ;
    SHAPE ABUTMENT ;
    PORT
      LAYER metal2 ;
      RECT 9.655 0.000 9.725 0.210 ;
    END
  END rw0_wd_in[63]
  PIN rw0_wd_in[64]
    DIRECTION INPUT ;
    USE SIGNAL ;
    SHAPE ABUTMENT ;
    PORT
      LAYER metal2 ;
      RECT 10.225 0.000 10.295 0.210 ;
    END
  END rw0_wd_in[64]
  PIN rw0_wd_in[65]
    DIRECTION INPUT ;
    USE SIGNAL ;
    SHAPE ABUTMENT ;
    PORT
      LAYER metal2 ;
      RECT 10.795 0.000 10.865 0.210 ;
    END
  END rw0_wd_in[65]
  PIN rw0_wd_in[66]
    DIRECTION INPUT ;
    USE SIGNAL ;
    SHAPE ABUTMENT ;
    PORT
      LAYER metal2 ;
      RECT 11.365 0.000 11.435 0.210 ;
    END
  END rw0_wd_in[66]
  PIN rw0_wd_in[67]
    DIRECTION INPUT ;
    USE SIGNAL ;
    SHAPE ABUTMENT ;
    PORT
      LAYER metal2 ;
      RECT 11.935 0.000 12.005 0.210 ;
    END
  END rw0_wd_in[67]
  PIN rw0_wd_in[68]
    DIRECTION INPUT ;
    USE SIGNAL ;
    SHAPE ABUTMENT ;
    PORT
      LAYER metal2 ;
      RECT 12.505 0.000 12.575 0.210 ;
    END
  END rw0_wd_in[68]
  PIN rw0_wd_in[69]
    DIRECTION INPUT ;
    USE SIGNAL ;
    SHAPE ABUTMENT ;
    PORT
      LAYER metal2 ;
      RECT 13.075 0.000 13.145 0.210 ;
    END
  END rw0_wd_in[69]
  PIN rw0_wd_in[70]
    DIRECTION INPUT ;
    USE SIGNAL ;
    SHAPE ABUTMENT ;
    PORT
      LAYER metal2 ;
      RECT 13.645 0.000 13.715 0.210 ;
    END
  END rw0_wd_in[70]
  PIN rw0_wd_in[71]
    DIRECTION INPUT ;
    USE SIGNAL ;
    SHAPE ABUTMENT ;
    PORT
      LAYER metal2 ;
      RECT 14.215 0.000 14.285 0.210 ;
    END
  END rw0_wd_in[71]
  PIN rw0_wd_in[72]
    DIRECTION INPUT ;
    USE SIGNAL ;
    SHAPE ABUTMENT ;
    PORT
      LAYER metal2 ;
      RECT 14.785 0.000 14.855 0.210 ;
    END
  END rw0_wd_in[72]
  PIN rw0_wd_in[73]
    DIRECTION INPUT ;
    USE SIGNAL ;
    SHAPE ABUTMENT ;
    PORT
      LAYER metal2 ;
      RECT 15.355 0.000 15.425 0.210 ;
    END
  END rw0_wd_in[73]
  PIN rw0_wd_in[74]
    DIRECTION INPUT ;
    USE SIGNAL ;
    SHAPE ABUTMENT ;
    PORT
      LAYER metal2 ;
      RECT 15.925 0.000 15.995 0.210 ;
    END
  END rw0_wd_in[74]
  PIN rw0_wd_in[75]
    DIRECTION INPUT ;
    USE SIGNAL ;
    SHAPE ABUTMENT ;
    PORT
      LAYER metal2 ;
      RECT 16.495 0.000 16.565 0.210 ;
    END
  END rw0_wd_in[75]
  PIN rw0_wd_in[76]
    DIRECTION INPUT ;
    USE SIGNAL ;
    SHAPE ABUTMENT ;
    PORT
      LAYER metal2 ;
      RECT 17.065 0.000 17.135 0.210 ;
    END
  END rw0_wd_in[76]
  PIN rw0_wd_in[77]
    DIRECTION INPUT ;
    USE SIGNAL ;
    SHAPE ABUTMENT ;
    PORT
      LAYER metal2 ;
      RECT 17.635 0.000 17.705 0.210 ;
    END
  END rw0_wd_in[77]
  PIN rw0_wd_in[78]
    DIRECTION INPUT ;
    USE SIGNAL ;
    SHAPE ABUTMENT ;
    PORT
      LAYER metal2 ;
      RECT 18.205 0.000 18.275 0.210 ;
    END
  END rw0_wd_in[78]
  PIN rw0_wd_in[79]
    DIRECTION INPUT ;
    USE SIGNAL ;
    SHAPE ABUTMENT ;
    PORT
      LAYER metal2 ;
      RECT 18.775 0.000 18.845 0.210 ;
    END
  END rw0_wd_in[79]
  PIN rw0_wd_in[80]
    DIRECTION INPUT ;
    USE SIGNAL ;
    SHAPE ABUTMENT ;
    PORT
      LAYER metal2 ;
      RECT 19.345 0.000 19.415 0.210 ;
    END
  END rw0_wd_in[80]
  PIN rw0_wd_in[81]
    DIRECTION INPUT ;
    USE SIGNAL ;
    SHAPE ABUTMENT ;
    PORT
      LAYER metal2 ;
      RECT 19.915 0.000 19.985 0.210 ;
    END
  END rw0_wd_in[81]
  PIN rw0_wd_in[82]
    DIRECTION INPUT ;
    USE SIGNAL ;
    SHAPE ABUTMENT ;
    PORT
      LAYER metal2 ;
      RECT 20.485 0.000 20.555 0.210 ;
    END
  END rw0_wd_in[82]
  PIN rw0_wd_in[83]
    DIRECTION INPUT ;
    USE SIGNAL ;
    SHAPE ABUTMENT ;
    PORT
      LAYER metal2 ;
      RECT 21.055 0.000 21.125 0.210 ;
    END
  END rw0_wd_in[83]
  PIN rw0_wd_in[84]
    DIRECTION INPUT ;
    USE SIGNAL ;
    SHAPE ABUTMENT ;
    PORT
      LAYER metal2 ;
      RECT 21.625 0.000 21.695 0.210 ;
    END
  END rw0_wd_in[84]
  PIN rw0_wd_in[85]
    DIRECTION INPUT ;
    USE SIGNAL ;
    SHAPE ABUTMENT ;
    PORT
      LAYER metal2 ;
      RECT 22.195 0.000 22.265 0.210 ;
    END
  END rw0_wd_in[85]
  PIN rw0_wd_in[86]
    DIRECTION INPUT ;
    USE SIGNAL ;
    SHAPE ABUTMENT ;
    PORT
      LAYER metal2 ;
      RECT 22.765 0.000 22.835 0.210 ;
    END
  END rw0_wd_in[86]
  PIN rw0_wd_in[87]
    DIRECTION INPUT ;
    USE SIGNAL ;
    SHAPE ABUTMENT ;
    PORT
      LAYER metal2 ;
      RECT 23.335 0.000 23.405 0.210 ;
    END
  END rw0_wd_in[87]
  PIN rw0_wd_in[88]
    DIRECTION INPUT ;
    USE SIGNAL ;
    SHAPE ABUTMENT ;
    PORT
      LAYER metal2 ;
      RECT 23.905 0.000 23.975 0.210 ;
    END
  END rw0_wd_in[88]
  PIN rw0_wd_in[89]
    DIRECTION INPUT ;
    USE SIGNAL ;
    SHAPE ABUTMENT ;
    PORT
      LAYER metal2 ;
      RECT 24.475 0.000 24.545 0.210 ;
    END
  END rw0_wd_in[89]
  PIN rw0_wd_in[90]
    DIRECTION INPUT ;
    USE SIGNAL ;
    SHAPE ABUTMENT ;
    PORT
      LAYER metal2 ;
      RECT 25.045 0.000 25.115 0.210 ;
    END
  END rw0_wd_in[90]
  PIN rw0_wd_in[91]
    DIRECTION INPUT ;
    USE SIGNAL ;
    SHAPE ABUTMENT ;
    PORT
      LAYER metal2 ;
      RECT 25.615 0.000 25.685 0.210 ;
    END
  END rw0_wd_in[91]
  PIN rw0_wd_in[92]
    DIRECTION INPUT ;
    USE SIGNAL ;
    SHAPE ABUTMENT ;
    PORT
      LAYER metal2 ;
      RECT 26.185 0.000 26.255 0.210 ;
    END
  END rw0_wd_in[92]
  PIN rw0_wd_in[93]
    DIRECTION INPUT ;
    USE SIGNAL ;
    SHAPE ABUTMENT ;
    PORT
      LAYER metal2 ;
      RECT 26.755 0.000 26.825 0.210 ;
    END
  END rw0_wd_in[93]
  PIN rw0_wd_in[94]
    DIRECTION INPUT ;
    USE SIGNAL ;
    SHAPE ABUTMENT ;
    PORT
      LAYER metal2 ;
      RECT 27.325 0.000 27.395 0.210 ;
    END
  END rw0_wd_in[94]
  PIN rw0_wd_in[95]
    DIRECTION INPUT ;
    USE SIGNAL ;
    SHAPE ABUTMENT ;
    PORT
      LAYER metal2 ;
      RECT 27.895 0.000 27.965 0.210 ;
    END
  END rw0_wd_in[95]
  PIN rw0_rd_out[0]
    DIRECTION OUTPUT ;
    USE SIGNAL ;
    SHAPE ABUTMENT ;
    PORT
      LAYER metal2 ;
      RECT 28.465 0.000 28.535 0.210 ;
    END
  END rw0_rd_out[0]
  PIN rw0_rd_out[1]
    DIRECTION OUTPUT ;
    USE SIGNAL ;
    SHAPE ABUTMENT ;
    PORT
      LAYER metal2 ;
      RECT 29.035 0.000 29.105 0.210 ;
    END
  END rw0_rd_out[1]
  PIN rw0_rd_out[2]
    DIRECTION OUTPUT ;
    USE SIGNAL ;
    SHAPE ABUTMENT ;
    PORT
      LAYER metal2 ;
      RECT 29.605 0.000 29.675 0.210 ;
    END
  END rw0_rd_out[2]
  PIN rw0_rd_out[3]
    DIRECTION OUTPUT ;
    USE SIGNAL ;
    SHAPE ABUTMENT ;
    PORT
      LAYER metal2 ;
      RECT 30.175 0.000 30.245 0.210 ;
    END
  END rw0_rd_out[3]
  PIN rw0_rd_out[4]
    DIRECTION OUTPUT ;
    USE SIGNAL ;
    SHAPE ABUTMENT ;
    PORT
      LAYER metal2 ;
      RECT 30.745 0.000 30.815 0.210 ;
    END
  END rw0_rd_out[4]
  PIN rw0_rd_out[5]
    DIRECTION OUTPUT ;
    USE SIGNAL ;
    SHAPE ABUTMENT ;
    PORT
      LAYER metal2 ;
      RECT 31.315 0.000 31.385 0.210 ;
    END
  END rw0_rd_out[5]
  PIN rw0_rd_out[6]
    DIRECTION OUTPUT ;
    USE SIGNAL ;
    SHAPE ABUTMENT ;
    PORT
      LAYER metal2 ;
      RECT 31.885 0.000 31.955 0.210 ;
    END
  END rw0_rd_out[6]
  PIN rw0_rd_out[7]
    DIRECTION OUTPUT ;
    USE SIGNAL ;
    SHAPE ABUTMENT ;
    PORT
      LAYER metal2 ;
      RECT 32.455 0.000 32.525 0.210 ;
    END
  END rw0_rd_out[7]
  PIN rw0_rd_out[8]
    DIRECTION OUTPUT ;
    USE SIGNAL ;
    SHAPE ABUTMENT ;
    PORT
      LAYER metal2 ;
      RECT 33.025 0.000 33.095 0.210 ;
    END
  END rw0_rd_out[8]
  PIN rw0_rd_out[9]
    DIRECTION OUTPUT ;
    USE SIGNAL ;
    SHAPE ABUTMENT ;
    PORT
      LAYER metal2 ;
      RECT 33.595 0.000 33.665 0.210 ;
    END
  END rw0_rd_out[9]
  PIN rw0_rd_out[10]
    DIRECTION OUTPUT ;
    USE SIGNAL ;
    SHAPE ABUTMENT ;
    PORT
      LAYER metal2 ;
      RECT 34.165 0.000 34.235 0.210 ;
    END
  END rw0_rd_out[10]
  PIN rw0_rd_out[11]
    DIRECTION OUTPUT ;
    USE SIGNAL ;
    SHAPE ABUTMENT ;
    PORT
      LAYER metal2 ;
      RECT 34.735 0.000 34.805 0.210 ;
    END
  END rw0_rd_out[11]
  PIN rw0_rd_out[12]
    DIRECTION OUTPUT ;
    USE SIGNAL ;
    SHAPE ABUTMENT ;
    PORT
      LAYER metal2 ;
      RECT 35.305 0.000 35.375 0.210 ;
    END
  END rw0_rd_out[12]
  PIN rw0_rd_out[13]
    DIRECTION OUTPUT ;
    USE SIGNAL ;
    SHAPE ABUTMENT ;
    PORT
      LAYER metal2 ;
      RECT 35.875 0.000 35.945 0.210 ;
    END
  END rw0_rd_out[13]
  PIN rw0_rd_out[14]
    DIRECTION OUTPUT ;
    USE SIGNAL ;
    SHAPE ABUTMENT ;
    PORT
      LAYER metal2 ;
      RECT 36.445 0.000 36.515 0.210 ;
    END
  END rw0_rd_out[14]
  PIN rw0_rd_out[15]
    DIRECTION OUTPUT ;
    USE SIGNAL ;
    SHAPE ABUTMENT ;
    PORT
      LAYER metal2 ;
      RECT 37.015 0.000 37.085 0.210 ;
    END
  END rw0_rd_out[15]
  PIN rw0_rd_out[16]
    DIRECTION OUTPUT ;
    USE SIGNAL ;
    SHAPE ABUTMENT ;
    PORT
      LAYER metal2 ;
      RECT 37.585 0.000 37.655 0.210 ;
    END
  END rw0_rd_out[16]
  PIN rw0_rd_out[17]
    DIRECTION OUTPUT ;
    USE SIGNAL ;
    SHAPE ABUTMENT ;
    PORT
      LAYER metal2 ;
      RECT 38.155 0.000 38.225 0.210 ;
    END
  END rw0_rd_out[17]
  PIN rw0_rd_out[18]
    DIRECTION OUTPUT ;
    USE SIGNAL ;
    SHAPE ABUTMENT ;
    PORT
      LAYER metal2 ;
      RECT 38.725 0.000 38.795 0.210 ;
    END
  END rw0_rd_out[18]
  PIN rw0_rd_out[19]
    DIRECTION OUTPUT ;
    USE SIGNAL ;
    SHAPE ABUTMENT ;
    PORT
      LAYER metal2 ;
      RECT 39.295 0.000 39.365 0.210 ;
    END
  END rw0_rd_out[19]
  PIN rw0_rd_out[20]
    DIRECTION OUTPUT ;
    USE SIGNAL ;
    SHAPE ABUTMENT ;
    PORT
      LAYER metal2 ;
      RECT 39.865 0.000 39.935 0.210 ;
    END
  END rw0_rd_out[20]
  PIN rw0_rd_out[21]
    DIRECTION OUTPUT ;
    USE SIGNAL ;
    SHAPE ABUTMENT ;
    PORT
      LAYER metal2 ;
      RECT 40.435 0.000 40.505 0.210 ;
    END
  END rw0_rd_out[21]
  PIN rw0_rd_out[22]
    DIRECTION OUTPUT ;
    USE SIGNAL ;
    SHAPE ABUTMENT ;
    PORT
      LAYER metal2 ;
      RECT 41.005 0.000 41.075 0.210 ;
    END
  END rw0_rd_out[22]
  PIN rw0_rd_out[23]
    DIRECTION OUTPUT ;
    USE SIGNAL ;
    SHAPE ABUTMENT ;
    PORT
      LAYER metal2 ;
      RECT 41.575 0.000 41.645 0.210 ;
    END
  END rw0_rd_out[23]
  PIN rw0_rd_out[24]
    DIRECTION OUTPUT ;
    USE SIGNAL ;
    SHAPE ABUTMENT ;
    PORT
      LAYER metal2 ;
      RECT 42.145 0.000 42.215 0.210 ;
    END
  END rw0_rd_out[24]
  PIN rw0_rd_out[25]
    DIRECTION OUTPUT ;
    USE SIGNAL ;
    SHAPE ABUTMENT ;
    PORT
      LAYER metal2 ;
      RECT 42.715 0.000 42.785 0.210 ;
    END
  END rw0_rd_out[25]
  PIN rw0_rd_out[26]
    DIRECTION OUTPUT ;
    USE SIGNAL ;
    SHAPE ABUTMENT ;
    PORT
      LAYER metal2 ;
      RECT 43.285 0.000 43.355 0.210 ;
    END
  END rw0_rd_out[26]
  PIN rw0_rd_out[27]
    DIRECTION OUTPUT ;
    USE SIGNAL ;
    SHAPE ABUTMENT ;
    PORT
      LAYER metal2 ;
      RECT 43.855 0.000 43.925 0.210 ;
    END
  END rw0_rd_out[27]
  PIN rw0_rd_out[28]
    DIRECTION OUTPUT ;
    USE SIGNAL ;
    SHAPE ABUTMENT ;
    PORT
      LAYER metal2 ;
      RECT 44.425 0.000 44.495 0.210 ;
    END
  END rw0_rd_out[28]
  PIN rw0_rd_out[29]
    DIRECTION OUTPUT ;
    USE SIGNAL ;
    SHAPE ABUTMENT ;
    PORT
      LAYER metal2 ;
      RECT 44.995 0.000 45.065 0.210 ;
    END
  END rw0_rd_out[29]
  PIN rw0_rd_out[30]
    DIRECTION OUTPUT ;
    USE SIGNAL ;
    SHAPE ABUTMENT ;
    PORT
      LAYER metal2 ;
      RECT 45.565 0.000 45.635 0.210 ;
    END
  END rw0_rd_out[30]
  PIN rw0_rd_out[31]
    DIRECTION OUTPUT ;
    USE SIGNAL ;
    SHAPE ABUTMENT ;
    PORT
      LAYER metal2 ;
      RECT 46.135 0.000 46.205 0.210 ;
    END
  END rw0_rd_out[31]
  PIN rw0_rd_out[32]
    DIRECTION OUTPUT ;
    USE SIGNAL ;
    SHAPE ABUTMENT ;
    PORT
      LAYER metal2 ;
      RECT 46.705 0.000 46.775 0.210 ;
    END
  END rw0_rd_out[32]
  PIN rw0_rd_out[33]
    DIRECTION OUTPUT ;
    USE SIGNAL ;
    SHAPE ABUTMENT ;
    PORT
      LAYER metal2 ;
      RECT 47.275 0.000 47.345 0.210 ;
    END
  END rw0_rd_out[33]
  PIN rw0_rd_out[34]
    DIRECTION OUTPUT ;
    USE SIGNAL ;
    SHAPE ABUTMENT ;
    PORT
      LAYER metal2 ;
      RECT 47.845 0.000 47.915 0.210 ;
    END
  END rw0_rd_out[34]
  PIN rw0_rd_out[35]
    DIRECTION OUTPUT ;
    USE SIGNAL ;
    SHAPE ABUTMENT ;
    PORT
      LAYER metal2 ;
      RECT 48.415 0.000 48.485 0.210 ;
    END
  END rw0_rd_out[35]
  PIN rw0_rd_out[36]
    DIRECTION OUTPUT ;
    USE SIGNAL ;
    SHAPE ABUTMENT ;
    PORT
      LAYER metal2 ;
      RECT 48.985 0.000 49.055 0.210 ;
    END
  END rw0_rd_out[36]
  PIN rw0_rd_out[37]
    DIRECTION OUTPUT ;
    USE SIGNAL ;
    SHAPE ABUTMENT ;
    PORT
      LAYER metal2 ;
      RECT 49.555 0.000 49.625 0.210 ;
    END
  END rw0_rd_out[37]
  PIN rw0_rd_out[38]
    DIRECTION OUTPUT ;
    USE SIGNAL ;
    SHAPE ABUTMENT ;
    PORT
      LAYER metal2 ;
      RECT 50.125 0.000 50.195 0.210 ;
    END
  END rw0_rd_out[38]
  PIN rw0_rd_out[39]
    DIRECTION OUTPUT ;
    USE SIGNAL ;
    SHAPE ABUTMENT ;
    PORT
      LAYER metal2 ;
      RECT 50.695 0.000 50.765 0.210 ;
    END
  END rw0_rd_out[39]
  PIN rw0_rd_out[40]
    DIRECTION OUTPUT ;
    USE SIGNAL ;
    SHAPE ABUTMENT ;
    PORT
      LAYER metal2 ;
      RECT 51.265 0.000 51.335 0.210 ;
    END
  END rw0_rd_out[40]
  PIN rw0_rd_out[41]
    DIRECTION OUTPUT ;
    USE SIGNAL ;
    SHAPE ABUTMENT ;
    PORT
      LAYER metal2 ;
      RECT 51.835 0.000 51.905 0.210 ;
    END
  END rw0_rd_out[41]
  PIN rw0_rd_out[42]
    DIRECTION OUTPUT ;
    USE SIGNAL ;
    SHAPE ABUTMENT ;
    PORT
      LAYER metal2 ;
      RECT 52.405 0.000 52.475 0.210 ;
    END
  END rw0_rd_out[42]
  PIN rw0_rd_out[43]
    DIRECTION OUTPUT ;
    USE SIGNAL ;
    SHAPE ABUTMENT ;
    PORT
      LAYER metal2 ;
      RECT 52.975 0.000 53.045 0.210 ;
    END
  END rw0_rd_out[43]
  PIN rw0_rd_out[44]
    DIRECTION OUTPUT ;
    USE SIGNAL ;
    SHAPE ABUTMENT ;
    PORT
      LAYER metal2 ;
      RECT 53.545 0.000 53.615 0.210 ;
    END
  END rw0_rd_out[44]
  PIN rw0_rd_out[45]
    DIRECTION OUTPUT ;
    USE SIGNAL ;
    SHAPE ABUTMENT ;
    PORT
      LAYER metal2 ;
      RECT 54.115 0.000 54.185 0.210 ;
    END
  END rw0_rd_out[45]
  PIN rw0_rd_out[46]
    DIRECTION OUTPUT ;
    USE SIGNAL ;
    SHAPE ABUTMENT ;
    PORT
      LAYER metal2 ;
      RECT 54.685 0.000 54.755 0.210 ;
    END
  END rw0_rd_out[46]
  PIN rw0_rd_out[47]
    DIRECTION OUTPUT ;
    USE SIGNAL ;
    SHAPE ABUTMENT ;
    PORT
      LAYER metal2 ;
      RECT 55.255 0.000 55.325 0.210 ;
    END
  END rw0_rd_out[47]
  PIN rw0_rd_out[48]
    DIRECTION OUTPUT ;
    USE SIGNAL ;
    SHAPE ABUTMENT ;
    PORT
      LAYER metal2 ;
      RECT 28.465 78.190 28.535 78.400 ;
    END
  END rw0_rd_out[48]
  PIN rw0_rd_out[49]
    DIRECTION OUTPUT ;
    USE SIGNAL ;
    SHAPE ABUTMENT ;
    PORT
      LAYER metal2 ;
      RECT 29.035 78.190 29.105 78.400 ;
    END
  END rw0_rd_out[49]
  PIN rw0_rd_out[50]
    DIRECTION OUTPUT ;
    USE SIGNAL ;
    SHAPE ABUTMENT ;
    PORT
      LAYER metal2 ;
      RECT 29.605 78.190 29.675 78.400 ;
    END
  END rw0_rd_out[50]
  PIN rw0_rd_out[51]
    DIRECTION OUTPUT ;
    USE SIGNAL ;
    SHAPE ABUTMENT ;
    PORT
      LAYER metal2 ;
      RECT 30.175 78.190 30.245 78.400 ;
    END
  END rw0_rd_out[51]
  PIN rw0_rd_out[52]
    DIRECTION OUTPUT ;
    USE SIGNAL ;
    SHAPE ABUTMENT ;
    PORT
      LAYER metal2 ;
      RECT 30.745 78.190 30.815 78.400 ;
    END
  END rw0_rd_out[52]
  PIN rw0_rd_out[53]
    DIRECTION OUTPUT ;
    USE SIGNAL ;
    SHAPE ABUTMENT ;
    PORT
      LAYER metal2 ;
      RECT 31.315 78.190 31.385 78.400 ;
    END
  END rw0_rd_out[53]
  PIN rw0_rd_out[54]
    DIRECTION OUTPUT ;
    USE SIGNAL ;
    SHAPE ABUTMENT ;
    PORT
      LAYER metal2 ;
      RECT 31.885 78.190 31.955 78.400 ;
    END
  END rw0_rd_out[54]
  PIN rw0_rd_out[55]
    DIRECTION OUTPUT ;
    USE SIGNAL ;
    SHAPE ABUTMENT ;
    PORT
      LAYER metal2 ;
      RECT 32.455 78.190 32.525 78.400 ;
    END
  END rw0_rd_out[55]
  PIN rw0_rd_out[56]
    DIRECTION OUTPUT ;
    USE SIGNAL ;
    SHAPE ABUTMENT ;
    PORT
      LAYER metal2 ;
      RECT 33.025 78.190 33.095 78.400 ;
    END
  END rw0_rd_out[56]
  PIN rw0_rd_out[57]
    DIRECTION OUTPUT ;
    USE SIGNAL ;
    SHAPE ABUTMENT ;
    PORT
      LAYER metal2 ;
      RECT 33.595 78.190 33.665 78.400 ;
    END
  END rw0_rd_out[57]
  PIN rw0_rd_out[58]
    DIRECTION OUTPUT ;
    USE SIGNAL ;
    SHAPE ABUTMENT ;
    PORT
      LAYER metal2 ;
      RECT 34.165 78.190 34.235 78.400 ;
    END
  END rw0_rd_out[58]
  PIN rw0_rd_out[59]
    DIRECTION OUTPUT ;
    USE SIGNAL ;
    SHAPE ABUTMENT ;
    PORT
      LAYER metal2 ;
      RECT 34.735 78.190 34.805 78.400 ;
    END
  END rw0_rd_out[59]
  PIN rw0_rd_out[60]
    DIRECTION OUTPUT ;
    USE SIGNAL ;
    SHAPE ABUTMENT ;
    PORT
      LAYER metal2 ;
      RECT 35.305 78.190 35.375 78.400 ;
    END
  END rw0_rd_out[60]
  PIN rw0_rd_out[61]
    DIRECTION OUTPUT ;
    USE SIGNAL ;
    SHAPE ABUTMENT ;
    PORT
      LAYER metal2 ;
      RECT 35.875 78.190 35.945 78.400 ;
    END
  END rw0_rd_out[61]
  PIN rw0_rd_out[62]
    DIRECTION OUTPUT ;
    USE SIGNAL ;
    SHAPE ABUTMENT ;
    PORT
      LAYER metal2 ;
      RECT 36.445 78.190 36.515 78.400 ;
    END
  END rw0_rd_out[62]
  PIN rw0_rd_out[63]
    DIRECTION OUTPUT ;
    USE SIGNAL ;
    SHAPE ABUTMENT ;
    PORT
      LAYER metal2 ;
      RECT 37.015 78.190 37.085 78.400 ;
    END
  END rw0_rd_out[63]
  PIN rw0_rd_out[64]
    DIRECTION OUTPUT ;
    USE SIGNAL ;
    SHAPE ABUTMENT ;
    PORT
      LAYER metal2 ;
      RECT 37.585 78.190 37.655 78.400 ;
    END
  END rw0_rd_out[64]
  PIN rw0_rd_out[65]
    DIRECTION OUTPUT ;
    USE SIGNAL ;
    SHAPE ABUTMENT ;
    PORT
      LAYER metal2 ;
      RECT 38.155 78.190 38.225 78.400 ;
    END
  END rw0_rd_out[65]
  PIN rw0_rd_out[66]
    DIRECTION OUTPUT ;
    USE SIGNAL ;
    SHAPE ABUTMENT ;
    PORT
      LAYER metal2 ;
      RECT 38.725 78.190 38.795 78.400 ;
    END
  END rw0_rd_out[66]
  PIN rw0_rd_out[67]
    DIRECTION OUTPUT ;
    USE SIGNAL ;
    SHAPE ABUTMENT ;
    PORT
      LAYER metal2 ;
      RECT 39.295 78.190 39.365 78.400 ;
    END
  END rw0_rd_out[67]
  PIN rw0_rd_out[68]
    DIRECTION OUTPUT ;
    USE SIGNAL ;
    SHAPE ABUTMENT ;
    PORT
      LAYER metal2 ;
      RECT 39.865 78.190 39.935 78.400 ;
    END
  END rw0_rd_out[68]
  PIN rw0_rd_out[69]
    DIRECTION OUTPUT ;
    USE SIGNAL ;
    SHAPE ABUTMENT ;
    PORT
      LAYER metal2 ;
      RECT 40.435 78.190 40.505 78.400 ;
    END
  END rw0_rd_out[69]
  PIN rw0_rd_out[70]
    DIRECTION OUTPUT ;
    USE SIGNAL ;
    SHAPE ABUTMENT ;
    PORT
      LAYER metal2 ;
      RECT 41.005 78.190 41.075 78.400 ;
    END
  END rw0_rd_out[70]
  PIN rw0_rd_out[71]
    DIRECTION OUTPUT ;
    USE SIGNAL ;
    SHAPE ABUTMENT ;
    PORT
      LAYER metal2 ;
      RECT 41.575 78.190 41.645 78.400 ;
    END
  END rw0_rd_out[71]
  PIN rw0_rd_out[72]
    DIRECTION OUTPUT ;
    USE SIGNAL ;
    SHAPE ABUTMENT ;
    PORT
      LAYER metal2 ;
      RECT 42.145 78.190 42.215 78.400 ;
    END
  END rw0_rd_out[72]
  PIN rw0_rd_out[73]
    DIRECTION OUTPUT ;
    USE SIGNAL ;
    SHAPE ABUTMENT ;
    PORT
      LAYER metal2 ;
      RECT 42.715 78.190 42.785 78.400 ;
    END
  END rw0_rd_out[73]
  PIN rw0_rd_out[74]
    DIRECTION OUTPUT ;
    USE SIGNAL ;
    SHAPE ABUTMENT ;
    PORT
      LAYER metal2 ;
      RECT 43.285 78.190 43.355 78.400 ;
    END
  END rw0_rd_out[74]
  PIN rw0_rd_out[75]
    DIRECTION OUTPUT ;
    USE SIGNAL ;
    SHAPE ABUTMENT ;
    PORT
      LAYER metal2 ;
      RECT 43.855 78.190 43.925 78.400 ;
    END
  END rw0_rd_out[75]
  PIN rw0_rd_out[76]
    DIRECTION OUTPUT ;
    USE SIGNAL ;
    SHAPE ABUTMENT ;
    PORT
      LAYER metal2 ;
      RECT 44.425 78.190 44.495 78.400 ;
    END
  END rw0_rd_out[76]
  PIN rw0_rd_out[77]
    DIRECTION OUTPUT ;
    USE SIGNAL ;
    SHAPE ABUTMENT ;
    PORT
      LAYER metal2 ;
      RECT 44.995 78.190 45.065 78.400 ;
    END
  END rw0_rd_out[77]
  PIN rw0_rd_out[78]
    DIRECTION OUTPUT ;
    USE SIGNAL ;
    SHAPE ABUTMENT ;
    PORT
      LAYER metal2 ;
      RECT 45.565 78.190 45.635 78.400 ;
    END
  END rw0_rd_out[78]
  PIN rw0_rd_out[79]
    DIRECTION OUTPUT ;
    USE SIGNAL ;
    SHAPE ABUTMENT ;
    PORT
      LAYER metal2 ;
      RECT 46.135 78.190 46.205 78.400 ;
    END
  END rw0_rd_out[79]
  PIN rw0_rd_out[80]
    DIRECTION OUTPUT ;
    USE SIGNAL ;
    SHAPE ABUTMENT ;
    PORT
      LAYER metal2 ;
      RECT 46.705 78.190 46.775 78.400 ;
    END
  END rw0_rd_out[80]
  PIN rw0_rd_out[81]
    DIRECTION OUTPUT ;
    USE SIGNAL ;
    SHAPE ABUTMENT ;
    PORT
      LAYER metal2 ;
      RECT 47.275 78.190 47.345 78.400 ;
    END
  END rw0_rd_out[81]
  PIN rw0_rd_out[82]
    DIRECTION OUTPUT ;
    USE SIGNAL ;
    SHAPE ABUTMENT ;
    PORT
      LAYER metal2 ;
      RECT 47.845 78.190 47.915 78.400 ;
    END
  END rw0_rd_out[82]
  PIN rw0_rd_out[83]
    DIRECTION OUTPUT ;
    USE SIGNAL ;
    SHAPE ABUTMENT ;
    PORT
      LAYER metal2 ;
      RECT 48.415 78.190 48.485 78.400 ;
    END
  END rw0_rd_out[83]
  PIN rw0_rd_out[84]
    DIRECTION OUTPUT ;
    USE SIGNAL ;
    SHAPE ABUTMENT ;
    PORT
      LAYER metal2 ;
      RECT 48.985 78.190 49.055 78.400 ;
    END
  END rw0_rd_out[84]
  PIN rw0_rd_out[85]
    DIRECTION OUTPUT ;
    USE SIGNAL ;
    SHAPE ABUTMENT ;
    PORT
      LAYER metal2 ;
      RECT 49.555 78.190 49.625 78.400 ;
    END
  END rw0_rd_out[85]
  PIN rw0_rd_out[86]
    DIRECTION OUTPUT ;
    USE SIGNAL ;
    SHAPE ABUTMENT ;
    PORT
      LAYER metal2 ;
      RECT 50.125 78.190 50.195 78.400 ;
    END
  END rw0_rd_out[86]
  PIN rw0_rd_out[87]
    DIRECTION OUTPUT ;
    USE SIGNAL ;
    SHAPE ABUTMENT ;
    PORT
      LAYER metal2 ;
      RECT 50.695 78.190 50.765 78.400 ;
    END
  END rw0_rd_out[87]
  PIN rw0_rd_out[88]
    DIRECTION OUTPUT ;
    USE SIGNAL ;
    SHAPE ABUTMENT ;
    PORT
      LAYER metal2 ;
      RECT 51.265 78.190 51.335 78.400 ;
    END
  END rw0_rd_out[88]
  PIN rw0_rd_out[89]
    DIRECTION OUTPUT ;
    USE SIGNAL ;
    SHAPE ABUTMENT ;
    PORT
      LAYER metal2 ;
      RECT 51.835 78.190 51.905 78.400 ;
    END
  END rw0_rd_out[89]
  PIN rw0_rd_out[90]
    DIRECTION OUTPUT ;
    USE SIGNAL ;
    SHAPE ABUTMENT ;
    PORT
      LAYER metal2 ;
      RECT 52.405 78.190 52.475 78.400 ;
    END
  END rw0_rd_out[90]
  PIN rw0_rd_out[91]
    DIRECTION OUTPUT ;
    USE SIGNAL ;
    SHAPE ABUTMENT ;
    PORT
      LAYER metal2 ;
      RECT 52.975 78.190 53.045 78.400 ;
    END
  END rw0_rd_out[91]
  PIN rw0_rd_out[92]
    DIRECTION OUTPUT ;
    USE SIGNAL ;
    SHAPE ABUTMENT ;
    PORT
      LAYER metal2 ;
      RECT 53.545 78.190 53.615 78.400 ;
    END
  END rw0_rd_out[92]
  PIN rw0_rd_out[93]
    DIRECTION OUTPUT ;
    USE SIGNAL ;
    SHAPE ABUTMENT ;
    PORT
      LAYER metal2 ;
      RECT 54.115 78.190 54.185 78.400 ;
    END
  END rw0_rd_out[93]
  PIN rw0_rd_out[94]
    DIRECTION OUTPUT ;
    USE SIGNAL ;
    SHAPE ABUTMENT ;
    PORT
      LAYER metal2 ;
      RECT 54.685 78.190 54.755 78.400 ;
    END
  END rw0_rd_out[94]
  PIN rw0_rd_out[95]
    DIRECTION OUTPUT ;
    USE SIGNAL ;
    SHAPE ABUTMENT ;
    PORT
      LAYER metal2 ;
      RECT 55.255 78.190 55.325 78.400 ;
    END
  END rw0_rd_out[95]
  PIN rw0_addr_in[0]
    DIRECTION INPUT ;
    USE SIGNAL ;
    SHAPE ABUTMENT ;
    PORT
      LAYER metal3 ;
      RECT 0.000 68.005 0.210 68.075 ;
    END
  END rw0_addr_in[0]
  PIN rw0_addr_in[1]
    DIRECTION INPUT ;
    USE SIGNAL ;
    SHAPE ABUTMENT ;
    PORT
      LAYER metal3 ;
      RECT 0.000 69.405 0.210 69.475 ;
    END
  END rw0_addr_in[1]
  PIN rw0_addr_in[2]
    DIRECTION INPUT ;
    USE SIGNAL ;
    SHAPE ABUTMENT ;
    PORT
      LAYER metal3 ;
      RECT 0.000 70.805 0.210 70.875 ;
    END
  END rw0_addr_in[2]
  PIN rw0_addr_in[3]
    DIRECTION INPUT ;
    USE SIGNAL ;
    SHAPE ABUTMENT ;
    PORT
      LAYER metal3 ;
      RECT 73.130 68.005 73.340 68.075 ;
    END
  END rw0_addr_in[3]
  PIN rw0_addr_in[4]
    DIRECTION INPUT ;
    USE SIGNAL ;
    SHAPE ABUTMENT ;
    PORT
      LAYER metal3 ;
      RECT 73.130 69.405 73.340 69.475 ;
    END
  END rw0_addr_in[4]
  PIN rw0_addr_in[5]
    DIRECTION INPUT ;
    USE SIGNAL ;
    SHAPE ABUTMENT ;
    PORT
      LAYER metal3 ;
      RECT 73.130 70.805 73.340 70.875 ;
    END
  END rw0_addr_in[5]
  PIN rw0_we_in
    DIRECTION INPUT ;
    USE SIGNAL ;
    SHAPE ABUTMENT ;
    PORT
      LAYER metal2 ;
      RECT 55.825 78.190 55.895 78.400 ;
    END
  END rw0_we_in
  PIN rw0_ce_in
    DIRECTION INPUT ;
    USE SIGNAL ;
    SHAPE ABUTMENT ;
    PORT
      LAYER metal2 ;
      RECT 56.395 78.190 56.465 78.400 ;
    END
  END rw0_ce_in
  PIN rw0_clk
    DIRECTION INPUT ;
    USE SIGNAL ;
    SHAPE ABUTMENT ;
    PORT
      LAYER metal2 ;
      RECT 56.965 78.190 57.035 78.400 ;
    END
  END rw0_clk
  PIN VSS
    DIRECTION INOUT ;
    USE GROUND ;
    PORT
      LAYER metal4 ;
      RECT 1.000 0.840 1.280 77.560 ;
      RECT 3.240 0.840 3.520 77.560 ;
      RECT 5.480 0.840 5.760 77.560 ;
      RECT 7.720 0.840 8.000 77.560 ;
      RECT 9.960 0.840 10.240 77.560 ;
      RECT 12.200 0.840 12.480 77.560 ;
      RECT 14.440 0.840 14.720 77.560 ;
      RECT 16.680 0.840 16.960 77.560 ;
      RECT 18.920 0.840 19.200 77.560 ;
      RECT 21.160 0.840 21.440 77.560 ;
      RECT 23.400 0.840 23.680 77.560 ;
      RECT 25.640 0.840 25.920 77.560 ;
      RECT 27.880 0.840 28.160 77.560 ;
      RECT 30.120 0.840 30.400 77.560 ;
      RECT 32.360 0.840 32.640 77.560 ;
      RECT 34.600 0.840 34.880 77.560 ;
      RECT 36.840 0.840 37.120 77.560 ;
      RECT 39.080 0.840 39.360 77.560 ;
      RECT 41.320 0.840 41.600 77.560 ;
      RECT 43.560 0.840 43.840 77.560 ;
      RECT 45.800 0.840 46.080 77.560 ;
      RECT 48.040 0.840 48.320 77.560 ;
      RECT 50.280 0.840 50.560 77.560 ;
      RECT 52.520 0.840 52.800 77.560 ;
      RECT 54.760 0.840 55.040 77.560 ;
      RECT 57.000 0.840 57.280 77.560 ;
      RECT 59.240 0.840 59.520 77.560 ;
      RECT 61.480 0.840 61.760 77.560 ;
      RECT 63.720 0.840 64.000 77.560 ;
      RECT 65.960 0.840 66.240 77.560 ;
      RECT 68.200 0.840 68.480 77.560 ;
      RECT 70.440 0.840 70.720 77.560 ;
      RECT 72.680 0.840 72.960 77.560 ;
    END
  END VSS
  PIN VDD
    DIRECTION INOUT ;
    USE POWER ;
    PORT
      LAYER metal4 ;
      RECT 1.000 0.840 1.280 77.560 ;
      RECT 3.240 0.840 3.520 77.560 ;
      RECT 5.480 0.840 5.760 77.560 ;
      RECT 7.720 0.840 8.000 77.560 ;
      RECT 9.960 0.840 10.240 77.560 ;
      RECT 12.200 0.840 12.480 77.560 ;
      RECT 14.440 0.840 14.720 77.560 ;
      RECT 16.680 0.840 16.960 77.560 ;
      RECT 18.920 0.840 19.200 77.560 ;
      RECT 21.160 0.840 21.440 77.560 ;
      RECT 23.400 0.840 23.680 77.560 ;
      RECT 25.640 0.840 25.920 77.560 ;
      RECT 27.880 0.840 28.160 77.560 ;
      RECT 30.120 0.840 30.400 77.560 ;
      RECT 32.360 0.840 32.640 77.560 ;
      RECT 34.600 0.840 34.880 77.560 ;
      RECT 36.840 0.840 37.120 77.560 ;
      RECT 39.080 0.840 39.360 77.560 ;
      RECT 41.320 0.840 41.600 77.560 ;
      RECT 43.560 0.840 43.840 77.560 ;
      RECT 45.800 0.840 46.080 77.560 ;
      RECT 48.040 0.840 48.320 77.560 ;
      RECT 50.280 0.840 50.560 77.560 ;
      RECT 52.520 0.840 52.800 77.560 ;
      RECT 54.760 0.840 55.040 77.560 ;
      RECT 57.000 0.840 57.280 77.560 ;
      RECT 59.240 0.840 59.520 77.560 ;
      RECT 61.480 0.840 61.760 77.560 ;
      RECT 63.720 0.840 64.000 77.560 ;
      RECT 65.960 0.840 66.240 77.560 ;
      RECT 68.200 0.840 68.480 77.560 ;
      RECT 70.440 0.840 70.720 77.560 ;
      RECT 72.680 0.840 72.960 77.560 ;
    END
  END VDD
  OBS
    LAYER metal1 ;
    RECT 0 0 73.340 78.400 ;
    LAYER metal2 ;
    RECT 0 0 73.340 78.400 ;
    LAYER metal3 ;
    RECT 0 0 73.340 78.400 ;
    LAYER metal4 ;
    RECT 0 0 73.340 78.400 ;
    LAYER OVERLAP ;
    RECT 0 0 73.340 78.400 ;
  END
END ht45_blackparrot_64x96

END LIBRARY
